One B-rep face of a CAD part: STEP entity #741.
In plain terms, the planar face has unit normal (1, 0, 0).
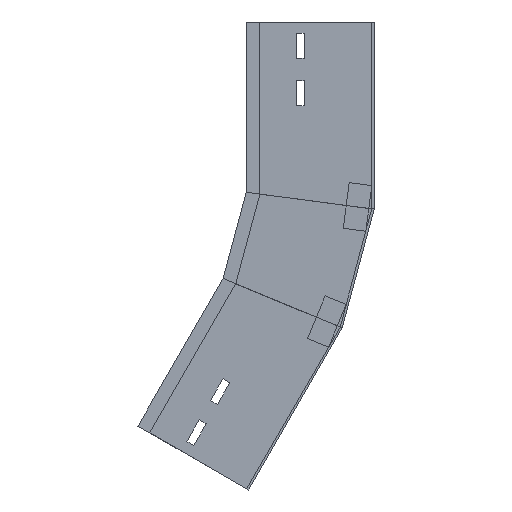
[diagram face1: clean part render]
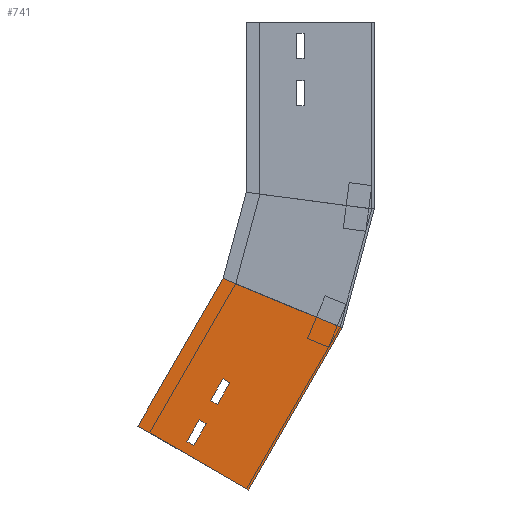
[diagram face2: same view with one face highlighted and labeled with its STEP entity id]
Its self-contained STEP definition (entity closure, numbers rounded to 3 decimals):
#36 = ORIENTED_EDGE ( 'NONE', *, *, #1026, .T. ) ;
#44 = VECTOR ( 'NONE', #1256, 1000. ) ;
#47 = DIRECTION ( 'NONE',  ( 0., 1., 0. ) ) ;
#52 = LINE ( 'NONE', #1357, #615 ) ;
#62 = PLANE ( 'NONE',  #1221 ) ;
#85 = CARTESIAN_POINT ( 'NONE',  ( 0., 61.5, -73.505 ) ) ;
#113 = CARTESIAN_POINT ( 'NONE',  ( 0., 61.5, -9.835 ) ) ;
#115 = CARTESIAN_POINT ( 'NONE',  ( 0., 68.5, -9.835 ) ) ;
#117 = CARTESIAN_POINT ( 'NONE',  ( 0., 112.5, 0. ) ) ;
#123 = EDGE_CURVE ( 'NONE', #1397, #746, #900, .T. ) ;
#148 = VECTOR ( 'NONE', #47, 1000. ) ;
#155 = VECTOR ( 'NONE', #1031, 1000. ) ;
#158 = EDGE_CURVE ( 'NONE', #1171, #1017, #1046, .T. ) ;
#176 = ORIENTED_EDGE ( 'NONE', *, *, #123, .T. ) ;
#204 = VERTEX_POINT ( 'NONE', #514 ) ;
#207 = DIRECTION ( 'NONE',  ( 0., 0., 1. ) ) ;
#212 = EDGE_CURVE ( 'NONE', #474, #317, #960, .T. ) ;
#235 = EDGE_CURVE ( 'NONE', #1228, #474, #817, .T. ) ;
#241 = EDGE_LOOP ( 'NONE', ( #661, #642, #176, #273 ) ) ;
#259 = VECTOR ( 'NONE', #1106, 1000. ) ;
#273 = ORIENTED_EDGE ( 'NONE', *, *, #800, .T. ) ;
#274 = CARTESIAN_POINT ( 'NONE',  ( 0., 68.5, -31.835 ) ) ;
#275 = VECTOR ( 'NONE', #436, 1000. ) ;
#282 = VECTOR ( 'NONE', #829, 1000. ) ;
#289 = DIRECTION ( 'NONE',  ( 0., 1., 0. ) ) ;
#306 = EDGE_CURVE ( 'NONE', #1388, #1060, #949, .T. ) ;
#317 = VERTEX_POINT ( 'NONE', #1190 ) ;
#319 = CARTESIAN_POINT ( 'NONE',  ( 0., 112.5, 0. ) ) ;
#320 = DIRECTION ( 'NONE',  ( 0., -1., 0. ) ) ;
#324 = VECTOR ( 'NONE', #702, 1000. ) ;
#426 = EDGE_CURVE ( 'NONE', #1060, #880, #52, .T. ) ;
#436 = DIRECTION ( 'NONE',  ( 0., -1., 0. ) ) ;
#474 = VERTEX_POINT ( 'NONE', #1087 ) ;
#514 = CARTESIAN_POINT ( 'NONE',  ( 0., 0., 0. ) ) ;
#568 = CARTESIAN_POINT ( 'NONE',  ( 0., 0., 0. ) ) ;
#575 = DIRECTION ( 'NONE',  ( 0., 0., -1. ) ) ;
#593 = ORIENTED_EDGE ( 'NONE', *, *, #1287, .T. ) ;
#596 = EDGE_CURVE ( 'NONE', #1017, #1397, #795, .T. ) ;
#615 = VECTOR ( 'NONE', #1226, 1000. ) ;
#624 = VERTEX_POINT ( 'NONE', #804 ) ;
#631 = CARTESIAN_POINT ( 'NONE',  ( 0., 61.5, -51.505 ) ) ;
#635 = ORIENTED_EDGE ( 'NONE', *, *, #212, .F. ) ;
#642 = ORIENTED_EDGE ( 'NONE', *, *, #596, .T. ) ;
#657 = LINE ( 'NONE', #1437, #259 ) ;
#661 = ORIENTED_EDGE ( 'NONE', *, *, #158, .T. ) ;
#663 = CARTESIAN_POINT ( 'NONE',  ( 0., 68.5, -73.505 ) ) ;
#686 = LINE ( 'NONE', #115, #44 ) ;
#694 = FACE_BOUND ( 'NONE', #241, .T. ) ;
#700 = CARTESIAN_POINT ( 'NONE',  ( 0., 61.5, -31.835 ) ) ;
#702 = DIRECTION ( 'NONE',  ( 0., 0., -1. ) ) ;
#741 = ADVANCED_FACE ( 'NONE', ( #694, #1010, #1129 ), #62, .F. ) ;
#746 = VERTEX_POINT ( 'NONE', #85 ) ;
#747 = CARTESIAN_POINT ( 'NONE',  ( 0., 68.5, -31.835 ) ) ;
#795 = LINE ( 'NONE', #1236, #1456 ) ;
#800 = EDGE_CURVE ( 'NONE', #746, #1171, #657, .T. ) ;
#804 = CARTESIAN_POINT ( 'NONE',  ( 0., 68.5, -9.835 ) ) ;
#806 = ORIENTED_EDGE ( 'NONE', *, *, #426, .T. ) ;
#810 = CARTESIAN_POINT ( 'NONE',  ( 0., 0., 0. ) ) ;
#813 = ORIENTED_EDGE ( 'NONE', *, *, #1261, .F. ) ;
#817 = LINE ( 'NONE', #117, #324 ) ;
#829 = DIRECTION ( 'NONE',  ( 0., 1., 0. ) ) ;
#840 = EDGE_LOOP ( 'NONE', ( #1115, #813, #1325, #635 ) ) ;
#880 = VERTEX_POINT ( 'NONE', #113 ) ;
#883 = CARTESIAN_POINT ( 'NONE',  ( 0., 0., 0. ) ) ;
#889 = EDGE_CURVE ( 'NONE', #204, #317, #1490, .T. ) ;
#900 = LINE ( 'NONE', #1130, #1379 ) ;
#919 = CARTESIAN_POINT ( 'NONE',  ( 0., 21.301, -161.796 ) ) ;
#926 = DIRECTION ( 'NONE',  ( 0., -0.991, -0.131 ) ) ;
#943 = CARTESIAN_POINT ( 'NONE',  ( 0., 68.5, -51.505 ) ) ;
#949 = LINE ( 'NONE', #274, #275 ) ;
#960 = LINE ( 'NONE', #919, #1034 ) ;
#1010 = FACE_OUTER_BOUND ( 'NONE', #840, .T. ) ;
#1017 = VERTEX_POINT ( 'NONE', #1356 ) ;
#1026 = EDGE_CURVE ( 'NONE', #624, #1388, #686, .T. ) ;
#1031 = DIRECTION ( 'NONE',  ( 0., 0., -1. ) ) ;
#1033 = EDGE_LOOP ( 'NONE', ( #593, #36, #1370, #806 ) ) ;
#1034 = VECTOR ( 'NONE', #926, 1000. ) ;
#1046 = LINE ( 'NONE', #943, #282 ) ;
#1060 = VERTEX_POINT ( 'NONE', #700 ) ;
#1087 = CARTESIAN_POINT ( 'NONE',  ( 0., 112.5, -149.789 ) ) ;
#1106 = DIRECTION ( 'NONE',  ( 0., 0., 1. ) ) ;
#1115 = ORIENTED_EDGE ( 'NONE', *, *, #235, .F. ) ;
#1117 = LINE ( 'NONE', #883, #1374 ) ;
#1129 = FACE_BOUND ( 'NONE', #1033, .T. ) ;
#1130 = CARTESIAN_POINT ( 'NONE',  ( 0., 68.5, -73.505 ) ) ;
#1171 = VERTEX_POINT ( 'NONE', #631 ) ;
#1190 = CARTESIAN_POINT ( 'NONE',  ( 0., 0., -164.6 ) ) ;
#1221 = AXIS2_PLACEMENT_3D ( 'NONE', #810, #1234, #207 ) ;
#1226 = DIRECTION ( 'NONE',  ( 0., 0., 1. ) ) ;
#1228 = VERTEX_POINT ( 'NONE', #319 ) ;
#1234 = DIRECTION ( 'NONE',  ( -1., 0., 0. ) ) ;
#1236 = CARTESIAN_POINT ( 'NONE',  ( 0., 68.5, -51.505 ) ) ;
#1256 = DIRECTION ( 'NONE',  ( 0., 0., -1. ) ) ;
#1261 = EDGE_CURVE ( 'NONE', #204, #1228, #1117, .T. ) ;
#1287 = EDGE_CURVE ( 'NONE', #880, #624, #1336, .T. ) ;
#1325 = ORIENTED_EDGE ( 'NONE', *, *, #889, .T. ) ;
#1329 = CARTESIAN_POINT ( 'NONE',  ( 0., 68.5, -9.835 ) ) ;
#1336 = LINE ( 'NONE', #1329, #148 ) ;
#1356 = CARTESIAN_POINT ( 'NONE',  ( 0., 68.5, -51.505 ) ) ;
#1357 = CARTESIAN_POINT ( 'NONE',  ( 0., 61.5, -9.835 ) ) ;
#1370 = ORIENTED_EDGE ( 'NONE', *, *, #306, .T. ) ;
#1374 = VECTOR ( 'NONE', #289, 1000. ) ;
#1379 = VECTOR ( 'NONE', #320, 1000. ) ;
#1388 = VERTEX_POINT ( 'NONE', #747 ) ;
#1397 = VERTEX_POINT ( 'NONE', #663 ) ;
#1437 = CARTESIAN_POINT ( 'NONE',  ( 0., 61.5, -51.505 ) ) ;
#1456 = VECTOR ( 'NONE', #575, 1000. ) ;
#1490 = LINE ( 'NONE', #568, #155 ) ;
